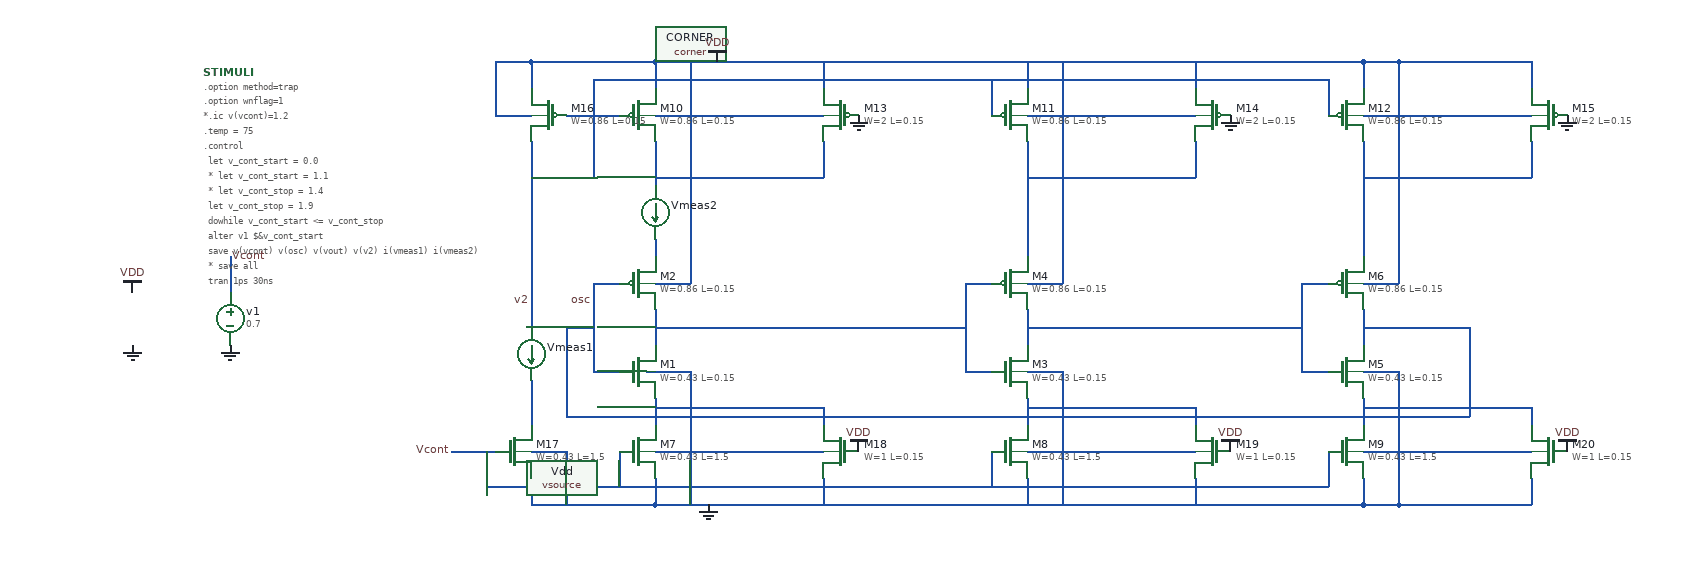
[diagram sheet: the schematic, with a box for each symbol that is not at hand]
v {xschem version=3.4.5 file_version=1.2
}
G {}
K {}
V {}
S {}
E {}
B 2 20 -1720 1940 -940 {flags=graph
y1=-0.05
y2=1.9
ypos1=0
ypos2=2
divy=5
subdivy=1
unity=1
x1=1.5596284e-08
x2=1.6440708e-08
divx=5
subdivx=4
xlabmag=1.0
ylabmag=1.0


dataset=-1
unitx=1
logx=0
logy=0
linewidth_mult=3




color=5
node=osc}
N 350 -670 350 -630 {
lab=Vcont}
N 830 -610 830 -570 {
lab=#net1}
N 760 -640 790 -640 {
lab=osc}
N 760 -640 760 -540 {
lab=osc}
N 760 -540 790 -540 {
lab=osc}
N 1250 -610 1250 -570 {
lab=#net2}
N 1180 -640 1210 -640 {
lab=#net1}
N 1180 -640 1180 -540 {
lab=#net1}
N 1180 -540 1210 -540 {
lab=#net1}
N 830 -590 1180 -590 {
lab=#net1}
N 1630 -610 1630 -570 {
lab=osc}
N 1560 -640 1590 -640 {
lab=#net2}
N 1560 -640 1560 -540 {
lab=#net2}
N 1560 -540 1590 -540 {
lab=#net2}
N 1250 -590 1560 -590 {
lab=#net2}
N 830 -420 830 -390 {
lab=GND}
N 830 -390 1630 -390 {
lab=GND}
N 1630 -420 1630 -390 {
lab=GND}
N 1250 -420 1250 -390 {
lab=GND}
N 1630 -590 1750 -590 {
lab=osc}
N 1750 -590 1750 -490 {
lab=osc}
N 730 -490 1750 -490 {
lab=osc}
N 730 -590 730 -490 {
lab=osc}
N 730 -590 760 -590 {
lab=osc}
N 830 -800 830 -750 {
lab=#net3}
N 830 -890 830 -860 {
lab=VDD}
N 830 -890 1630 -890 {
lab=VDD}
N 1630 -890 1630 -860 {
lab=VDD}
N 1250 -890 1250 -860 {
lab=VDD}
N 690 -890 690 -860 {
lab=VDD}
N 690 -890 830 -890 {
lab=VDD}
N 760 -830 760 -760 {
lab=v2}
N 690 -760 760 -760 {
lab=v2}
N 690 -420 690 -390 {
lab=GND}
N 690 -390 830 -390 {
lab=GND}
N 600 -450 650 -450 {
lab=Vcont}
N 1630 -510 1630 -480 {
lab=#net4}
N 1250 -510 1250 -480 {
lab=#net5}
N 830 -510 830 -480 {
lab=#net6}
N 830 -640 870 -640 {
lab=VDD}
N 870 -890 870 -640 {
lab=VDD}
N 830 -540 870 -540 {
lab=GND}
N 870 -540 870 -390 {
lab=GND}
N 830 -450 870 -450 {
lab=GND}
N 1250 -540 1290 -540 {
lab=GND}
N 1290 -540 1290 -390 {
lab=GND}
N 1250 -450 1290 -450 {
lab=GND}
N 1630 -540 1670 -540 {
lab=GND}
N 1670 -540 1670 -390 {
lab=GND}
N 1630 -390 1670 -390 {
lab=GND}
N 1630 -450 1670 -450 {
lab=GND}
N 730 -830 790 -830 {
lab=v2}
N 830 -830 870 -830 {
lab=VDD}
N 1250 -830 1290 -830 {
lab=VDD}
N 1250 -640 1290 -640 {
lab=VDD}
N 1290 -890 1290 -640 {
lab=VDD}
N 1630 -830 1670 -830 {
lab=VDD}
N 1630 -890 1670 -890 {
lab=VDD}
N 1670 -890 1670 -640 {
lab=VDD}
N 1630 -640 1670 -640 {
lab=VDD}
N 760 -870 760 -830 {
lab=v2}
N 760 -870 1590 -870 {
lab=v2}
N 1590 -870 1590 -830 {
lab=v2}
N 1210 -870 1210 -830 {
lab=v2}
N 640 -450 640 -410 {
lab=Vcont}
N 640 -410 1590 -410 {
lab=Vcont}
N 1590 -450 1590 -410 {
lab=Vcont}
N 1210 -450 1210 -410 {
lab=Vcont}
N 790 -450 790 -410 {
lab=Vcont}
N 650 -830 690 -830 {
lab=VDD}
N 650 -890 650 -830 {
lab=VDD}
N 650 -890 690 -890 {
lab=VDD}
N 690 -450 730 -450 {
lab=GND}
N 730 -450 730 -390 {
lab=GND}
N 690 -530 690 -480 {
lab=#net7}
N 690 -800 690 -590 {
lab=v2}
N 820 -540 830 -540 {
lab=GND}
N 1020 -890 1020 -860 {
lab=VDD}
N 870 -830 1020 -830 {
lab=VDD}
N 1020 -800 1020 -760 {
lab=#net3}
N 830 -760 1020 -760 {
lab=#net3}
N 1440 -890 1440 -860 {
lab=VDD}
N 1290 -830 1440 -830 {
lab=VDD}
N 1250 -760 1440 -760 {
lab=#net8}
N 1440 -800 1440 -760 {
lab=#net8}
N 1820 -890 1820 -860 {
lab=VDD}
N 1670 -830 1820 -830 {
lab=VDD}
N 1630 -760 1820 -760 {
lab=#net9}
N 1820 -800 1820 -760 {
lab=#net9}
N 1670 -890 1820 -890 {
lab=VDD}
N 830 -500 1020 -500 {
lab=#net6}
N 1020 -500 1020 -470 {
lab=#net6}
N 870 -450 1020 -450 {
lab=GND}
N 1020 -420 1020 -390 {
lab=GND}
N 1250 -500 1440 -500 {
lab=#net5}
N 1440 -500 1440 -470 {
lab=#net5}
N 1290 -450 1440 -450 {
lab=GND}
N 1440 -420 1440 -390 {
lab=GND}
N 1630 -500 1820 -500 {
lab=#net4}
N 1820 -500 1820 -470 {
lab=#net4}
N 1670 -450 1820 -450 {
lab=GND}
N 1820 -420 1820 -390 {
lab=GND}
N 1670 -390 1820 -390 {
lab=GND}
N 1630 -800 1630 -670 {
lab=#net9}
N 1250 -800 1250 -670 {
lab=#net8}
N 830 -690 830 -670 {
lab=#net10}
C {devices/vsource.sym} 240 -600 0 0 {name=Vdd value=1.8 savecurrent=false
* "pwl()"}
C {devices/gnd.sym} 240 -570 0 0 {name=l3 lab=GND}
C {devices/vdd.sym} 240 -630 0 0 {name=l4 lab=VDD}
C {devices/vsource.sym} 350 -600 0 0 {name=v1 value=0.7 savecurrent=false}
C {devices/gnd.sym} 350 -570 0 0 {name=l5 lab=GND}
C {devices/lab_pin.sym} 350 -670 0 1 {name=p1 sig_type=std_logic lab=Vcont}
C {sky130_fd_pr/corner.sym} 180 -880 0 0 {name=CORNER only_toplevel=false corner=tt}
C {devices/code.sym} 320 -878.75 0 0 {name=STIMULI only_toplevel=false value="

.option method=trap
.option wnflag=1


*.ic v(vcont)=1.2

.temp = 75

.control

  let v_cont_start = 0.0
  * let v_cont_start = 1.1
  * let v_cont_stop = 1.4
  let v_cont_stop = 1.9  

  dowhile v_cont_start <= v_cont_stop
    alter v1 $&v_cont_start
    save v(vcont) v(osc) v(vout) v(v2) i(vmeas1) i(vmeas2)
    * save all
    tran 1ps 30ns
    remzerovec
    write tb_current_starved_VCO4_5_\{$&v_cont_start\}.raw
    * write tb_current_starved_VCO4_5_.raw
    linearize v(osc)
    let filename = v_cont_start * 100
    wrdata /foss/designs/my_design/projects/pll/vco/xschem_ngspice/tb_current_starved_VCO4_5_\{$&filename\}.txt v(osc)
    set appendwrite

    reset
    let v_cont_start = v_cont_start + 0.1
  end
.endc


"}
C {devices/vdd.sym} 900 -890 0 0 {name=l1 lab=VDD}
C {devices/gnd.sym} 890 -390 0 0 {name=l2 lab=GND}
C {sky130_fd_pr/nfet_01v8.sym} 810 -540 0 0 {name=M1
L=0.15
W=0.43
nf=1 
mult=1
ad="'int((nf+1)/2) * W/nf * 0.29'" 
pd="'2*int((nf+1)/2) * (W/nf + 0.29)'"
as="'int((nf+2)/2) * W/nf * 0.29'" 
ps="'2*int((nf+2)/2) * (W/nf + 0.29)'"
nrd="'0.29 / W'" nrs="'0.29 / W'"
sa=0 sb=0 sd=0
model=nfet_01v8
spiceprefix=X
}
C {sky130_fd_pr/pfet_01v8.sym} 810 -640 0 0 {name=M2
L=0.15
W=0.86
nf=2
mult=1
ad="'int((nf+1)/2) * W/nf * 0.29'" 
pd="'2*int((nf+1)/2) * (W/nf + 0.29)'"
as="'int((nf+2)/2) * W/nf * 0.29'" 
ps="'2*int((nf+2)/2) * (W/nf + 0.29)'"
nrd="'0.29 / W'" nrs="'0.29 / W'"
sa=0 sb=0 sd=0
model=pfet_01v8
spiceprefix=X
}
C {sky130_fd_pr/nfet_01v8.sym} 1230 -540 0 0 {name=M3
L=0.15
W=0.43
nf=1 
mult=1
ad="'int((nf+1)/2) * W/nf * 0.29'" 
pd="'2*int((nf+1)/2) * (W/nf + 0.29)'"
as="'int((nf+2)/2) * W/nf * 0.29'" 
ps="'2*int((nf+2)/2) * (W/nf + 0.29)'"
nrd="'0.29 / W'" nrs="'0.29 / W'"
sa=0 sb=0 sd=0
model=nfet_01v8
spiceprefix=X
}
C {sky130_fd_pr/pfet_01v8.sym} 1230 -640 0 0 {name=M4
L=0.15
W=0.86
nf=2
mult=1
ad="'int((nf+1)/2) * W/nf * 0.29'" 
pd="'2*int((nf+1)/2) * (W/nf + 0.29)'"
as="'int((nf+2)/2) * W/nf * 0.29'" 
ps="'2*int((nf+2)/2) * (W/nf + 0.29)'"
nrd="'0.29 / W'" nrs="'0.29 / W'"
sa=0 sb=0 sd=0
model=pfet_01v8
spiceprefix=X
}
C {sky130_fd_pr/nfet_01v8.sym} 1610 -540 0 0 {name=M5
L=0.15
W=0.43
nf=1 
mult=1
ad="'int((nf+1)/2) * W/nf * 0.29'" 
pd="'2*int((nf+1)/2) * (W/nf + 0.29)'"
as="'int((nf+2)/2) * W/nf * 0.29'" 
ps="'2*int((nf+2)/2) * (W/nf + 0.29)'"
nrd="'0.29 / W'" nrs="'0.29 / W'"
sa=0 sb=0 sd=0
model=nfet_01v8
spiceprefix=X
}
C {sky130_fd_pr/pfet_01v8.sym} 1610 -640 0 0 {name=M6
L=0.15
W=0.86
nf=2
mult=1
ad="'int((nf+1)/2) * W/nf * 0.29'" 
pd="'2*int((nf+1)/2) * (W/nf + 0.29)'"
as="'int((nf+2)/2) * W/nf * 0.29'" 
ps="'2*int((nf+2)/2) * (W/nf + 0.29)'"
nrd="'0.29 / W'" nrs="'0.29 / W'"
sa=0 sb=0 sd=0
model=pfet_01v8
spiceprefix=X
}
C {sky130_fd_pr/nfet_01v8.sym} 810 -450 0 0 {name=M7
L=1.5
W=0.43
nf=1 
mult=1
ad="'int((nf+1)/2) * W/nf * 0.29'" 
pd="'2*int((nf+1)/2) * (W/nf + 0.29)'"
as="'int((nf+2)/2) * W/nf * 0.29'" 
ps="'2*int((nf+2)/2) * (W/nf + 0.29)'"
nrd="'0.29 / W'" nrs="'0.29 / W'"
sa=0 sb=0 sd=0
model=nfet_01v8
spiceprefix=X
}
C {sky130_fd_pr/nfet_01v8.sym} 1230 -450 0 0 {name=M8
L=1.5
W=0.43
nf=1 
mult=1
ad="'int((nf+1)/2) * W/nf * 0.29'" 
pd="'2*int((nf+1)/2) * (W/nf + 0.29)'"
as="'int((nf+2)/2) * W/nf * 0.29'" 
ps="'2*int((nf+2)/2) * (W/nf + 0.29)'"
nrd="'0.29 / W'" nrs="'0.29 / W'"
sa=0 sb=0 sd=0
model=nfet_01v8
spiceprefix=X
}
C {sky130_fd_pr/nfet_01v8.sym} 1610 -450 0 0 {name=M9
L=1.5
W=0.43
nf=1 
mult=1
ad="'int((nf+1)/2) * W/nf * 0.29'" 
pd="'2*int((nf+1)/2) * (W/nf + 0.29)'"
as="'int((nf+2)/2) * W/nf * 0.29'" 
ps="'2*int((nf+2)/2) * (W/nf + 0.29)'"
nrd="'0.29 / W'" nrs="'0.29 / W'"
sa=0 sb=0 sd=0
model=nfet_01v8
spiceprefix=X
}
C {sky130_fd_pr/pfet_01v8.sym} 810 -830 0 0 {name=M10
L=0.15
W=0.86
nf=2
mult=1
ad="'int((nf+1)/2) * W/nf * 0.29'" 
pd="'2*int((nf+1)/2) * (W/nf + 0.29)'"
as="'int((nf+2)/2) * W/nf * 0.29'" 
ps="'2*int((nf+2)/2) * (W/nf + 0.29)'"
nrd="'0.29 / W'" nrs="'0.29 / W'"
sa=0 sb=0 sd=0
model=pfet_01v8
spiceprefix=X
}
C {sky130_fd_pr/pfet_01v8.sym} 1230 -830 0 0 {name=M11
L=0.15
W=0.86
nf=2
mult=1
ad="'int((nf+1)/2) * W/nf * 0.29'" 
pd="'2*int((nf+1)/2) * (W/nf + 0.29)'"
as="'int((nf+2)/2) * W/nf * 0.29'" 
ps="'2*int((nf+2)/2) * (W/nf + 0.29)'"
nrd="'0.29 / W'" nrs="'0.29 / W'"
sa=0 sb=0 sd=0
model=pfet_01v8
spiceprefix=X
}
C {sky130_fd_pr/pfet_01v8.sym} 1610 -830 0 0 {name=M12
L=0.15
W=0.86
nf=2
mult=1
ad="'int((nf+1)/2) * W/nf * 0.29'" 
pd="'2*int((nf+1)/2) * (W/nf + 0.29)'"
as="'int((nf+2)/2) * W/nf * 0.29'" 
ps="'2*int((nf+2)/2) * (W/nf + 0.29)'"
nrd="'0.29 / W'" nrs="'0.29 / W'"
sa=0 sb=0 sd=0
model=pfet_01v8
spiceprefix=X
}
C {sky130_fd_pr/pfet_01v8.sym} 710 -830 0 1 {name=M16
L=0.15
W=0.86
nf=2
mult=1
ad="'int((nf+1)/2) * W/nf * 0.29'" 
pd="'2*int((nf+1)/2) * (W/nf + 0.29)'"
as="'int((nf+2)/2) * W/nf * 0.29'" 
ps="'2*int((nf+2)/2) * (W/nf + 0.29)'"
nrd="'0.29 / W'" nrs="'0.29 / W'"
sa=0 sb=0 sd=0
model=pfet_01v8
spiceprefix=X
}
C {sky130_fd_pr/nfet_01v8.sym} 670 -450 0 0 {name=M17
L=1.5
W=0.43
nf=1 
mult=1
ad="'int((nf+1)/2) * W/nf * 0.29'" 
pd="'2*int((nf+1)/2) * (W/nf + 0.29)'"
as="'int((nf+2)/2) * W/nf * 0.29'" 
ps="'2*int((nf+2)/2) * (W/nf + 0.29)'"
nrd="'0.29 / W'" nrs="'0.29 / W'"
sa=0 sb=0 sd=0
model=nfet_01v8
spiceprefix=X
}
C {devices/lab_pin.sym} 600 -450 0 0 {name=p2 sig_type=std_logic lab=Vcont}
C {devices/lab_pin.sym} 760 -620 0 0 {name=p3 sig_type=std_logic lab=osc}
C {devices/lab_pin.sym} 690 -620 0 0 {name=p4 sig_type=std_logic lab=v2}
C {devices/ammeter.sym} 690 -560 0 0 {name=Vmeas1 savecurrent=true spice_ignore=0}
C {sky130_fd_pr/pfet_01v8.sym} 1040 -830 0 1 {name=M13
L=0.15
W=2
nf=2
mult=1
ad="'int((nf+1)/2) * W/nf * 0.29'" 
pd="'2*int((nf+1)/2) * (W/nf + 0.29)'"
as="'int((nf+2)/2) * W/nf * 0.29'" 
ps="'2*int((nf+2)/2) * (W/nf + 0.29)'"
nrd="'0.29 / W'" nrs="'0.29 / W'"
sa=0 sb=0 sd=0
model=pfet_01v8
spiceprefix=X
}
C {devices/gnd.sym} 1060 -830 0 0 {name=l6 lab=GND}
C {sky130_fd_pr/pfet_01v8.sym} 1460 -830 0 1 {name=M14
L=0.15
W=2
nf=2
mult=1
ad="'int((nf+1)/2) * W/nf * 0.29'" 
pd="'2*int((nf+1)/2) * (W/nf + 0.29)'"
as="'int((nf+2)/2) * W/nf * 0.29'" 
ps="'2*int((nf+2)/2) * (W/nf + 0.29)'"
nrd="'0.29 / W'" nrs="'0.29 / W'"
sa=0 sb=0 sd=0
model=pfet_01v8
spiceprefix=X
}
C {devices/gnd.sym} 1480 -830 0 0 {name=l7 lab=GND}
C {sky130_fd_pr/pfet_01v8.sym} 1840 -830 0 1 {name=M15
L=0.15
W=2
nf=2
mult=1
ad="'int((nf+1)/2) * W/nf * 0.29'" 
pd="'2*int((nf+1)/2) * (W/nf + 0.29)'"
as="'int((nf+2)/2) * W/nf * 0.29'" 
ps="'2*int((nf+2)/2) * (W/nf + 0.29)'"
nrd="'0.29 / W'" nrs="'0.29 / W'"
sa=0 sb=0 sd=0
model=pfet_01v8
spiceprefix=X
}
C {devices/gnd.sym} 1860 -830 0 0 {name=l8 lab=GND}
C {sky130_fd_pr/nfet_01v8.sym} 1040 -450 0 1 {name=M18
L=0.15
W=1
nf=1 
mult=1
ad="'int((nf+1)/2) * W/nf * 0.29'" 
pd="'2*int((nf+1)/2) * (W/nf + 0.29)'"
as="'int((nf+2)/2) * W/nf * 0.29'" 
ps="'2*int((nf+2)/2) * (W/nf + 0.29)'"
nrd="'0.29 / W'" nrs="'0.29 / W'"
sa=0 sb=0 sd=0
model=nfet_01v8
spiceprefix=X
}
C {devices/vdd.sym} 1060 -450 0 0 {name=l9 lab=VDD}
C {sky130_fd_pr/nfet_01v8.sym} 1460 -450 0 1 {name=M19
L=0.15
W=1
nf=1 
mult=1
ad="'int((nf+1)/2) * W/nf * 0.29'" 
pd="'2*int((nf+1)/2) * (W/nf + 0.29)'"
as="'int((nf+2)/2) * W/nf * 0.29'" 
ps="'2*int((nf+2)/2) * (W/nf + 0.29)'"
nrd="'0.29 / W'" nrs="'0.29 / W'"
sa=0 sb=0 sd=0
model=nfet_01v8
spiceprefix=X
}
C {devices/vdd.sym} 1480 -450 0 0 {name=l10 lab=VDD}
C {sky130_fd_pr/nfet_01v8.sym} 1840 -450 0 1 {name=M20
L=0.15
W=1
nf=1 
mult=1
ad="'int((nf+1)/2) * W/nf * 0.29'" 
pd="'2*int((nf+1)/2) * (W/nf + 0.29)'"
as="'int((nf+2)/2) * W/nf * 0.29'" 
ps="'2*int((nf+2)/2) * (W/nf + 0.29)'"
nrd="'0.29 / W'" nrs="'0.29 / W'"
sa=0 sb=0 sd=0
model=nfet_01v8
spiceprefix=X
}
C {devices/vdd.sym} 1860 -450 0 0 {name=l11 lab=VDD}
C {devices/ammeter.sym} 830 -720 0 0 {name=Vmeas2 savecurrent=true spice_ignore=0}
